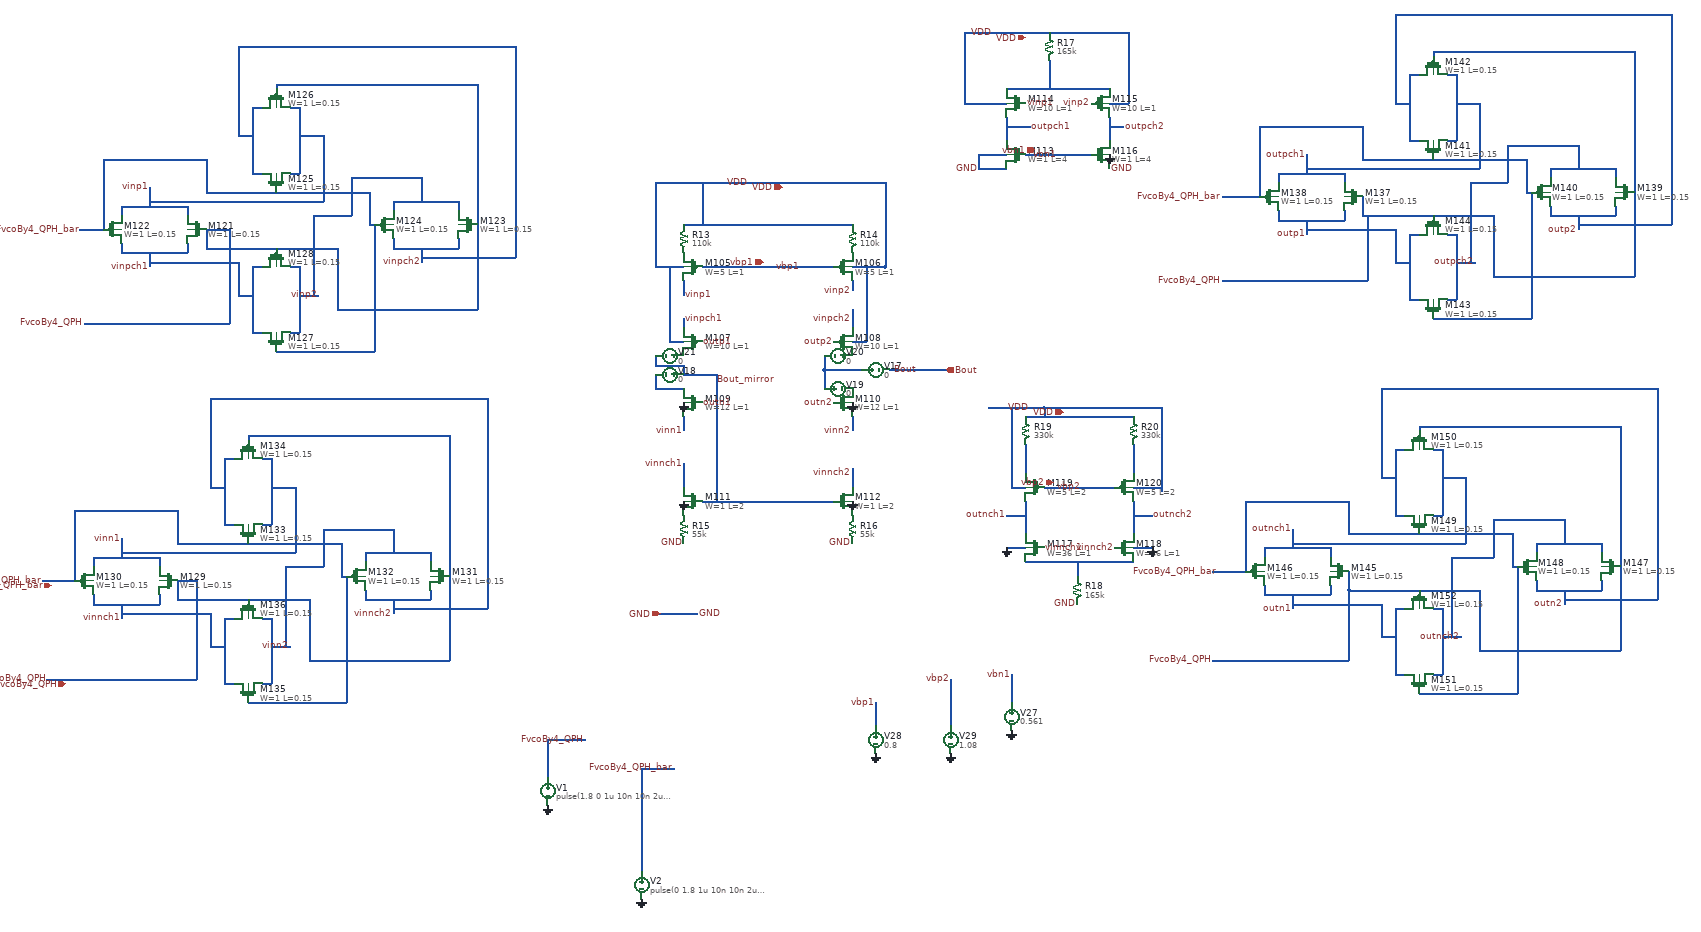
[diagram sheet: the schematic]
v {xschem version=2.9.9 file_version=1.2 }
G {}
K {}
V {}
S {}
E {}
N 3890 4550 4170 4550 { lab=vbp1}
N 3850 4460 4210 4460 { lab=VDD}
N 3790 4550 3850 4550 { lab=VDD}
N 3790 4370 3790 4550 { lab=VDD}
N 3790 4370 3880 4370 { lab=VDD}
N 3880 4370 4280 4370 { lab=VDD}
N 4210 4550 4280 4550 { lab=VDD}
N 4280 4530 4280 4550 { lab=VDD}
N 3890 5050 4170 5050 { lab=Bout_mirror}
N 3850 4780 3920 4780 { lab=Bout_mirror}
N 3920 4780 3920 4910 { lab=Bout_mirror}
N 3820 4710 3850 4710 { lab=VDD}
N 3820 4630 3820 4710 { lab=VDD}
N 4210 4710 4240 4710 { lab=VDD}
N 3890 4370 3890 4460 { lab=VDD}
N 4240 4630 4240 4710 { lab=VDD}
N 4280 4370 4280 4550 { lab=VDD}
N 4210 4770 4230 4770 { lab=#net1}
N 3790 4780 3790 4810 { lab=#net2}
N 3790 4810 3850 4810 { lab=#net2}
N 4150 4740 4150 4770 { lab=#net1}
N 3790 4740 3790 4760 { lab=Bout_mirror}
N 3790 4760 3850 4760 { lab=Bout_mirror}
N 3850 4760 3850 4780 { lab=Bout_mirror}
N 4150 4770 4150 4810 { lab=#net1}
N 4290 4770 4410 4770 { lab=Bout}
N 4580 4310 4720 4310 { lab=vbn1}
N 4760 4230 4760 4280 { lab=outpch2}
N 4540 4230 4540 4280 { lab=outpch1}
N 4540 4170 4760 4170 { lab=#net3}
N 4760 4200 4800 4200 { lab=VDD}
N 4800 4080 4800 4200 { lab=VDD}
N 4450 4200 4540 4200 { lab=VDD}
N 4450 4090 4450 4200 { lab=VDD}
N 4630 4110 4630 4170 { lab=#net3}
N 4450 4060 4450 4090 { lab=VDD}
N 4450 4050 4450 4060 { lab=VDD}
N 4450 4050 4630 4050 { lab=VDD}
N 4630 4050 4800 4050 { lab=VDD}
N 4800 4050 4800 4090 { lab=VDD}
N 4760 4250 4790 4250 { lab=outpch2}
N 4540 4250 4590 4250 { lab=outpch1}
N 4480 4310 4540 4310 { lab=GND}
N 4480 4310 4480 4340 { lab=GND}
N 4480 4340 4540 4340 { lab=GND}
N 4580 5180 4810 5180 { lab=#net4}
N 4690 5180 4690 5210 { lab=#net4}
N 4580 5050 4580 5120 { lab=outnch1}
N 4810 5050 4810 5120 { lab=outnch2}
N 4580 4930 4580 4990 { lab=#net5}
N 4810 4930 4810 4990 { lab=#net6}
N 4580 4870 4810 4870 { lab=VDD}
N 4500 4850 4620 4850 { lab=VDD}
N 4620 4850 4620 4870 { lab=VDD}
N 4620 5020 4770 5020 { lab=vbp2}
N 4540 5150 4580 5150 { lab=GND}
N 4810 5150 4850 5150 { lab=GND}
N 4810 5080 4850 5080 { lab=outnch2}
N 4540 5080 4580 5080 { lab=outnch1}
N 4550 4850 4550 5020 { lab=VDD}
N 4550 5020 4580 5020 { lab=VDD}
N 4620 4850 4870 4850 { lab=VDD}
N 4870 4850 4870 5030 { lab=VDD}
N 4810 5020 4870 5020 { lab=VDD}
N 3920 4910 3920 5050 { lab=Bout_mirror}
N 3850 4660 3850 4680 { lab=vinpch1}
N 4210 4660 4210 4680 { lab=vinpch2}
N 4240 4550 4240 4630 { lab=VDD}
N 3820 4550 3820 4630 { lab=VDD}
N 3850 4870 3850 4900 { lab=vinn1}
N 3850 4980 3850 5020 { lab=vinnch1}
N 4210 4870 4210 4900 { lab=vinn2}
N 4210 5000 4210 5020 { lab=vinnch2}
N 3850 4580 3850 4610 { lab=vinp1}
N 4210 4580 4210 4600 { lab=vinp2}
N 4210 4640 4210 4660 { lab=vinpch2}
N 4150 4770 4220 4770 { lab=#net1}
N 3850 4970 3850 4990 { lab=vinnch1}
N 4210 4980 4210 5010 { lab=vinnch2}
N 2790 4420 2790 4440 { lab=vinp1}
N 2650 4420 2790 4420 { lab=vinp1}
N 2650 4420 2650 4440 { lab=vinp1}
N 2790 4500 2790 4520 { lab=vinpch1}
N 2650 4520 2790 4520 { lab=vinpch1}
N 2650 4500 2650 4520 { lab=vinpch1}
N 2710 4520 2710 4550 { lab=vinpch1}
N 2710 4380 2710 4420 { lab=vinp1}
N 3370 4410 3370 4430 { lab=vinp2}
N 3230 4410 3370 4410 { lab=vinp2}
N 3230 4410 3230 4430 { lab=vinp2}
N 3370 4490 3370 4510 { lab=vinpch2}
N 3230 4510 3370 4510 { lab=vinpch2}
N 3230 4490 3230 4510 { lab=vinpch2}
N 3290 4510 3290 4540 { lab=vinpch2}
N 3290 4370 3290 4410 { lab=vinp2}
N 3010 4350 3030 4350 { lab=vinp1}
N 3030 4210 3030 4350 { lab=vinp1}
N 3010 4210 3030 4210 { lab=vinp1}
N 2930 4350 2950 4350 { lab=vinpch2}
N 2930 4210 2930 4350 { lab=vinpch2}
N 2930 4210 2950 4210 { lab=vinpch2}
N 2900 4270 2930 4270 { lab=vinpch2}
N 3030 4270 3070 4270 { lab=vinp1}
N 3010 4690 3030 4690 { lab=vinp2}
N 3030 4550 3030 4690 { lab=vinp2}
N 3010 4550 3030 4550 { lab=vinp2}
N 2930 4690 2950 4690 { lab=vinpch1}
N 2930 4550 2930 4690 { lab=vinpch1}
N 2930 4550 2950 4550 { lab=vinpch1}
N 2900 4610 2930 4610 { lab=vinpch1}
N 3030 4610 3070 4610 { lab=vinp2}
N 2610 4320 2610 4470 { lab=FvcoBy4_QPH_bar}
N 2610 4320 2830 4320 { lab=FvcoBy4_QPH_bar}
N 2830 4320 2830 4380 { lab=FvcoBy4_QPH_bar}
N 2830 4380 2830 4390 { lab=FvcoBy4_QPH_bar}
N 2830 4390 2980 4390 { lab=FvcoBy4_QPH_bar}
N 2980 4390 3180 4390 { lab=FvcoBy4_QPH_bar}
N 3180 4390 3180 4460 { lab=FvcoBy4_QPH_bar}
N 3180 4460 3190 4460 { lab=FvcoBy4_QPH_bar}
N 3190 4460 3190 4730 { lab=FvcoBy4_QPH_bar}
N 2980 4730 3190 4730 { lab=FvcoBy4_QPH_bar}
N 2830 4470 2830 4510 { lab=FvcoBy4_QPH}
N 2830 4510 2980 4510 { lab=FvcoBy4_QPH}
N 2980 4510 3110 4510 { lab=FvcoBy4_QPH}
N 3110 4510 3110 4640 { lab=FvcoBy4_QPH}
N 3110 4640 3410 4640 { lab=FvcoBy4_QPH}
N 3410 4460 3410 4640 { lab=FvcoBy4_QPH}
N 3410 4160 3410 4460 { lab=FvcoBy4_QPH}
N 2980 4160 3410 4160 { lab=FvcoBy4_QPH}
N 2980 4160 2980 4170 { lab=FvcoBy4_QPH}
N 2710 4410 3080 4410 { lab=vinp1}
N 3080 4270 3080 4410 { lab=vinp1}
N 3070 4270 3080 4270 { lab=vinp1}
N 2710 4540 2900 4540 { lab=vinpch1}
N 2900 4540 2900 4610 { lab=vinpch1}
N 3060 4440 3060 4610 { lab=vinp2}
N 3060 4440 3140 4440 { lab=vinp2}
N 3140 4360 3140 4440 { lab=vinp2}
N 3140 4360 3290 4360 { lab=vinp2}
N 3290 4360 3290 4370 { lab=vinp2}
N 2900 4080 2900 4270 { lab=vinpch2}
N 2900 4080 3490 4080 { lab=vinpch2}
N 3490 4080 3490 4530 { lab=vinpch2}
N 3290 4530 3490 4530 { lab=vinpch2}
N 2730 5170 2730 5190 { lab=vinn1}
N 2590 5170 2730 5170 { lab=vinn1}
N 2590 5170 2590 5190 { lab=vinn1}
N 2730 5250 2730 5270 { lab=vinnch1}
N 2590 5270 2730 5270 { lab=vinnch1}
N 2590 5250 2590 5270 { lab=vinnch1}
N 2650 5270 2650 5300 { lab=vinnch1}
N 2650 5130 2650 5170 { lab=vinn1}
N 3310 5160 3310 5180 { lab=vinn2}
N 3170 5160 3310 5160 { lab=vinn2}
N 3170 5160 3170 5180 { lab=vinn2}
N 3310 5240 3310 5260 { lab=vinnch2}
N 3170 5260 3310 5260 { lab=vinnch2}
N 3170 5240 3170 5260 { lab=vinnch2}
N 3230 5260 3230 5290 { lab=vinnch2}
N 3230 5120 3230 5160 { lab=vinn2}
N 2950 5100 2970 5100 { lab=vinn1}
N 2970 4960 2970 5100 { lab=vinn1}
N 2950 4960 2970 4960 { lab=vinn1}
N 2870 5100 2890 5100 { lab=vinnch2}
N 2870 4960 2870 5100 { lab=vinnch2}
N 2870 4960 2890 4960 { lab=vinnch2}
N 2840 5020 2870 5020 { lab=vinnch2}
N 2970 5020 3010 5020 { lab=vinn1}
N 2950 5440 2970 5440 { lab=vinn2}
N 2970 5300 2970 5440 { lab=vinn2}
N 2950 5300 2970 5300 { lab=vinn2}
N 2870 5440 2890 5440 { lab=vinnch1}
N 2870 5300 2870 5440 { lab=vinnch1}
N 2870 5300 2890 5300 { lab=vinnch1}
N 2840 5360 2870 5360 { lab=vinnch1}
N 2970 5360 3010 5360 { lab=vinn2}
N 2550 5070 2550 5220 { lab=FvcoBy4_QPH_bar}
N 2550 5070 2770 5070 { lab=FvcoBy4_QPH_bar}
N 2770 5070 2770 5130 { lab=FvcoBy4_QPH_bar}
N 2770 5130 2770 5140 { lab=FvcoBy4_QPH_bar}
N 2770 5140 2920 5140 { lab=FvcoBy4_QPH_bar}
N 2920 5140 3120 5140 { lab=FvcoBy4_QPH_bar}
N 3120 5140 3120 5210 { lab=FvcoBy4_QPH_bar}
N 3120 5210 3130 5210 { lab=FvcoBy4_QPH_bar}
N 3130 5210 3130 5480 { lab=FvcoBy4_QPH_bar}
N 2920 5480 3130 5480 { lab=FvcoBy4_QPH_bar}
N 2770 5220 2770 5260 { lab=FvcoBy4_QPH}
N 2770 5260 2920 5260 { lab=FvcoBy4_QPH}
N 2920 5260 3050 5260 { lab=FvcoBy4_QPH}
N 3050 5260 3050 5390 { lab=FvcoBy4_QPH}
N 3050 5390 3350 5390 { lab=FvcoBy4_QPH}
N 3350 5210 3350 5390 { lab=FvcoBy4_QPH}
N 3350 4910 3350 5210 { lab=FvcoBy4_QPH}
N 2920 4910 3350 4910 { lab=FvcoBy4_QPH}
N 2920 4910 2920 4920 { lab=FvcoBy4_QPH}
N 2650 5160 3020 5160 { lab=vinn1}
N 3020 5020 3020 5160 { lab=vinn1}
N 3010 5020 3020 5020 { lab=vinn1}
N 2650 5290 2840 5290 { lab=vinnch1}
N 2840 5290 2840 5360 { lab=vinnch1}
N 3000 5190 3000 5360 { lab=vinn2}
N 3000 5190 3080 5190 { lab=vinn2}
N 3080 5110 3080 5190 { lab=vinn2}
N 3080 5110 3230 5110 { lab=vinn2}
N 3230 5110 3230 5120 { lab=vinn2}
N 2840 4830 2840 5020 { lab=vinnch2}
N 2840 4830 3430 4830 { lab=vinnch2}
N 3430 4830 3430 5280 { lab=vinnch2}
N 3230 5280 3430 5280 { lab=vinnch2}
N 5260 4350 5260 4370 { lab=outpch1}
N 5120 4350 5260 4350 { lab=outpch1}
N 5120 4350 5120 4370 { lab=outpch1}
N 5260 4430 5260 4450 { lab=outp1}
N 5120 4450 5260 4450 { lab=outp1}
N 5120 4430 5120 4450 { lab=outp1}
N 5180 4450 5180 4480 { lab=outp1}
N 5180 4310 5180 4350 { lab=outpch1}
N 5840 4340 5840 4360 { lab=outpch2}
N 5700 4340 5840 4340 { lab=outpch2}
N 5700 4340 5700 4360 { lab=outpch2}
N 5840 4420 5840 4440 { lab=outp2}
N 5700 4440 5840 4440 { lab=outp2}
N 5700 4420 5700 4440 { lab=outp2}
N 5760 4440 5760 4470 { lab=outp2}
N 5760 4300 5760 4340 { lab=outpch2}
N 5480 4280 5500 4280 { lab=outpch1}
N 5500 4140 5500 4280 { lab=outpch1}
N 5480 4140 5500 4140 { lab=outpch1}
N 5400 4280 5420 4280 { lab=outp2}
N 5400 4140 5400 4280 { lab=outp2}
N 5400 4140 5420 4140 { lab=outp2}
N 5370 4200 5400 4200 { lab=outp2}
N 5500 4200 5540 4200 { lab=outpch1}
N 5480 4620 5500 4620 { lab=outpch2}
N 5500 4480 5500 4620 { lab=outpch2}
N 5480 4480 5500 4480 { lab=outpch2}
N 5400 4620 5420 4620 { lab=outp1}
N 5400 4480 5400 4620 { lab=outp1}
N 5400 4480 5420 4480 { lab=outp1}
N 5370 4540 5400 4540 { lab=outp1}
N 5500 4540 5540 4540 { lab=outpch2}
N 5080 4250 5080 4400 { lab=FvcoBy4_QPH_bar}
N 5080 4250 5300 4250 { lab=FvcoBy4_QPH_bar}
N 5300 4250 5300 4310 { lab=FvcoBy4_QPH_bar}
N 5300 4310 5300 4320 { lab=FvcoBy4_QPH_bar}
N 5300 4320 5450 4320 { lab=FvcoBy4_QPH_bar}
N 5450 4320 5650 4320 { lab=FvcoBy4_QPH_bar}
N 5650 4320 5650 4390 { lab=FvcoBy4_QPH_bar}
N 5650 4390 5660 4390 { lab=FvcoBy4_QPH_bar}
N 5660 4390 5660 4660 { lab=FvcoBy4_QPH_bar}
N 5450 4660 5660 4660 { lab=FvcoBy4_QPH_bar}
N 5300 4400 5300 4440 { lab=FvcoBy4_QPH}
N 5300 4440 5450 4440 { lab=FvcoBy4_QPH}
N 5450 4440 5580 4440 { lab=FvcoBy4_QPH}
N 5580 4440 5580 4570 { lab=FvcoBy4_QPH}
N 5580 4570 5880 4570 { lab=FvcoBy4_QPH}
N 5880 4390 5880 4570 { lab=FvcoBy4_QPH}
N 5880 4090 5880 4390 { lab=FvcoBy4_QPH}
N 5450 4090 5880 4090 { lab=FvcoBy4_QPH}
N 5450 4090 5450 4100 { lab=FvcoBy4_QPH}
N 5180 4340 5550 4340 { lab=outpch1}
N 5550 4200 5550 4340 { lab=outpch1}
N 5540 4200 5550 4200 { lab=outpch1}
N 5180 4470 5370 4470 { lab=outp1}
N 5370 4470 5370 4540 { lab=outp1}
N 5530 4370 5530 4540 { lab=outpch2}
N 5530 4370 5610 4370 { lab=outpch2}
N 5610 4290 5610 4370 { lab=outpch2}
N 5610 4290 5760 4290 { lab=outpch2}
N 5760 4290 5760 4300 { lab=outpch2}
N 5370 4010 5370 4200 { lab=outp2}
N 5370 4010 5960 4010 { lab=outp2}
N 5960 4010 5960 4460 { lab=outp2}
N 5760 4460 5960 4460 { lab=outp2}
N 5230 5150 5230 5170 { lab=outnch1}
N 5090 5150 5230 5150 { lab=outnch1}
N 5090 5150 5090 5170 { lab=outnch1}
N 5230 5230 5230 5250 { lab=outn1}
N 5090 5250 5230 5250 { lab=outn1}
N 5090 5230 5090 5250 { lab=outn1}
N 5150 5250 5150 5280 { lab=outn1}
N 5150 5110 5150 5150 { lab=outnch1}
N 5810 5140 5810 5160 { lab=outnch2}
N 5670 5140 5810 5140 { lab=outnch2}
N 5670 5140 5670 5160 { lab=outnch2}
N 5810 5220 5810 5240 { lab=outn2}
N 5670 5240 5810 5240 { lab=outn2}
N 5670 5220 5670 5240 { lab=outn2}
N 5730 5240 5730 5270 { lab=outn2}
N 5730 5100 5730 5140 { lab=outnch2}
N 5450 5080 5470 5080 { lab=outnch1}
N 5470 4940 5470 5080 { lab=outnch1}
N 5450 4940 5470 4940 { lab=outnch1}
N 5370 5080 5390 5080 { lab=outn2}
N 5370 4940 5370 5080 { lab=outn2}
N 5370 4940 5390 4940 { lab=outn2}
N 5340 5000 5370 5000 { lab=outn2}
N 5470 5000 5510 5000 { lab=outnch1}
N 5450 5420 5470 5420 { lab=outnch2}
N 5470 5280 5470 5420 { lab=outnch2}
N 5450 5280 5470 5280 { lab=outnch2}
N 5370 5420 5390 5420 { lab=outn1}
N 5370 5280 5370 5420 { lab=outn1}
N 5370 5280 5390 5280 { lab=outn1}
N 5340 5340 5370 5340 { lab=outn1}
N 5470 5340 5510 5340 { lab=outnch2}
N 5050 5050 5050 5200 { lab=FvcoBy4_QPH_bar}
N 5050 5050 5270 5050 { lab=FvcoBy4_QPH_bar}
N 5270 5050 5270 5110 { lab=FvcoBy4_QPH_bar}
N 5270 5110 5270 5120 { lab=FvcoBy4_QPH_bar}
N 5270 5120 5420 5120 { lab=FvcoBy4_QPH_bar}
N 5420 5120 5620 5120 { lab=FvcoBy4_QPH_bar}
N 5620 5120 5620 5190 { lab=FvcoBy4_QPH_bar}
N 5620 5190 5630 5190 { lab=FvcoBy4_QPH_bar}
N 5630 5190 5630 5460 { lab=FvcoBy4_QPH_bar}
N 5420 5460 5630 5460 { lab=FvcoBy4_QPH_bar}
N 5270 5200 5270 5240 { lab=FvcoBy4_QPH}
N 5270 5240 5420 5240 { lab=FvcoBy4_QPH}
N 5420 5240 5550 5240 { lab=FvcoBy4_QPH}
N 5550 5240 5550 5370 { lab=FvcoBy4_QPH}
N 5550 5370 5850 5370 { lab=FvcoBy4_QPH}
N 5850 5190 5850 5370 { lab=FvcoBy4_QPH}
N 5850 4890 5850 5190 { lab=FvcoBy4_QPH}
N 5420 4890 5850 4890 { lab=FvcoBy4_QPH}
N 5420 4890 5420 4900 { lab=FvcoBy4_QPH}
N 5150 5140 5520 5140 { lab=outnch1}
N 5520 5000 5520 5140 { lab=outnch1}
N 5510 5000 5520 5000 { lab=outnch1}
N 5150 5270 5340 5270 { lab=outn1}
N 5340 5270 5340 5340 { lab=outn1}
N 5490 5170 5490 5340 { lab=outnch2}
N 5500 5170 5580 5170 { lab=outnch2}
N 5580 5090 5580 5170 { lab=outnch2}
N 5580 5090 5730 5090 { lab=outnch2}
N 5730 5090 5730 5100 { lab=outnch2}
N 5340 4810 5340 5000 { lab=outn2}
N 5340 4810 5930 4810 { lab=outn2}
N 5930 4810 5930 5260 { lab=outn2}
N 5730 5260 5930 5260 { lab=outn2}
N 5490 5170 5540 5170 { lab=outnch2}
N 2830 4470 2880 4470 { lab=FvcoBy4_QPH}
N 2880 4470 2880 4670 { lab=FvcoBy4_QPH}
N 2570 4670 2880 4670 { lab=FvcoBy4_QPH}
N 2560 4470 2610 4470 { lab=FvcoBy4_QPH_bar}
N 2480 5220 2550 5220 { lab=FvcoBy4_QPH_bar}
N 2770 5220 2810 5220 { lab=FvcoBy4_QPH}
N 2810 5220 2810 5430 { lab=FvcoBy4_QPH}
N 2490 5430 2810 5430 { lab=FvcoBy4_QPH}
N 5000 4400 5080 4400 { lab=FvcoBy4_QPH_bar}
N 5310 4440 5310 4580 { lab=FvcoBy4_QPH}
N 5000 4580 5310 4580 { lab=FvcoBy4_QPH}
N 4980 5200 5050 5200 { lab=FvcoBy4_QPH_bar}
N 5270 5240 5270 5390 { lab=FvcoBy4_QPH}
N 4980 5390 5270 5390 { lab=FvcoBy4_QPH}
N 3790 5290 3880 5290 { lab=GND}
N 3760 5620 3830 5620 { lab=#net7}
N 4420 5430 4420 5530 { lab=vbp2}
N 3760 5620 3760 5840 { lab=#net7}
N 3560 5560 3560 5640 { lab=#net8}
N 3560 5560 3640 5560 { lab=#net8}
N 4260 5480 4260 5530 { lab=vbp1}
N 4550 5420 4550 5480 { lab=vbn1}
C {xschem_sky130/sky130_fd_pr/pfet_01v8_lvt.sym} 3870 4550 0 1 {name=M105
L=1
W=5
nf=1
mult=1
ad="'int((nf+1)/2) * W/nf * 0.29'" 
pd="'2*int((nf+1)/2) * (W/nf + 0.29)'"
as="'int((nf+2)/2) * W/nf * 0.29'" 
ps="'2*int((nf+2)/2) * (W/nf + 0.29)'"
nrd="'0.29 / W'" nrs="'0.29 / W'"
sa=0 sb=0 sd=0
model=pfet_01v8_lvt
spiceprefix=X
}
C {res.sym} 3850 4490 0 1 {name=R13
value=110k
footprint=1206
device=resistor
m=1}
C {xschem_sky130/sky130_fd_pr/pfet_01v8_lvt.sym} 4190 4550 0 0 {name=M106
L=1
W=5
nf=1
mult=1
ad="'int((nf+1)/2) * W/nf * 0.29'" 
pd="'2*int((nf+1)/2) * (W/nf + 0.29)'"
as="'int((nf+2)/2) * W/nf * 0.29'" 
ps="'2*int((nf+2)/2) * (W/nf + 0.29)'"
nrd="'0.29 / W'" nrs="'0.29 / W'"
sa=0 sb=0 sd=0
model=pfet_01v8_lvt
spiceprefix=X
}
C {res.sym} 4210 4490 0 0 {name=R14
value=110k
footprint=1206
device=resistor
m=1}
C {xschem_sky130/sky130_fd_pr/pfet_01v8_lvt.sym} 3870 4710 0 1 {name=M107
L=1
W=10
nf=1
mult=1
ad="'int((nf+1)/2) * W/nf * 0.29'" 
pd="'2*int((nf+1)/2) * (W/nf + 0.29)'"
as="'int((nf+2)/2) * W/nf * 0.29'" 
ps="'2*int((nf+2)/2) * (W/nf + 0.29)'"
nrd="'0.29 / W'" nrs="'0.29 / W'"
sa=0 sb=0 sd=0
model=pfet_01v8_lvt
spiceprefix=X
}
C {xschem_sky130/sky130_fd_pr/pfet_01v8_lvt.sym} 4190 4710 0 0 {name=M108
L=1
W=10
nf=1
mult=1
ad="'int((nf+1)/2) * W/nf * 0.29'" 
pd="'2*int((nf+1)/2) * (W/nf + 0.29)'"
as="'int((nf+2)/2) * W/nf * 0.29'" 
ps="'2*int((nf+2)/2) * (W/nf + 0.29)'"
nrd="'0.29 / W'" nrs="'0.29 / W'"
sa=0 sb=0 sd=0
model=pfet_01v8_lvt
spiceprefix=X
}
C {xschem_sky130/sky130_fd_pr/nfet_01v8_lvt.sym} 3870 4840 0 1 {name=M109
L=1
W=12
nf=1
mult=1
ad="'int((nf+1)/2) * W/nf * 0.29'" 
pd="'2*int((nf+1)/2) * (W/nf + 0.29)'"
as="'int((nf+2)/2) * W/nf * 0.29'" 
ps="'2*int((nf+2)/2) * (W/nf + 0.29)'"
nrd="'0.29 / W'" nrs="'0.29 / W'"
sa=0 sb=0 sd=0
model=nfet_01v8_lvt
spiceprefix=X
}
C {xschem_sky130/sky130_fd_pr/nfet_01v8_lvt.sym} 4190 4840 0 0 {name=M110
L=1
W=12
nf=1
mult=1
ad="'int((nf+1)/2) * W/nf * 0.29'" 
pd="'2*int((nf+1)/2) * (W/nf + 0.29)'"
as="'int((nf+2)/2) * W/nf * 0.29'" 
ps="'2*int((nf+2)/2) * (W/nf + 0.29)'"
nrd="'0.29 / W'" nrs="'0.29 / W'"
sa=0 sb=0 sd=0
model=nfet_01v8_lvt
spiceprefix=X
}
C {xschem_sky130/sky130_fd_pr/nfet_01v8_lvt.sym} 3870 5050 0 1 {name=M111
L=2
W=1
nf=1
mult=1
ad="'int((nf+1)/2) * W/nf * 0.29'" 
pd="'2*int((nf+1)/2) * (W/nf + 0.29)'"
as="'int((nf+2)/2) * W/nf * 0.29'" 
ps="'2*int((nf+2)/2) * (W/nf + 0.29)'"
nrd="'0.29 / W'" nrs="'0.29 / W'"
sa=0 sb=0 sd=0
model=nfet_01v8_lvt
spiceprefix=X
}
C {xschem_sky130/sky130_fd_pr/nfet_01v8_lvt.sym} 4190 5050 0 0 {name=M112
L=2
W=1
nf=1
mult=1
ad="'int((nf+1)/2) * W/nf * 0.29'" 
pd="'2*int((nf+1)/2) * (W/nf + 0.29)'"
as="'int((nf+2)/2) * W/nf * 0.29'" 
ps="'2*int((nf+2)/2) * (W/nf + 0.29)'"
nrd="'0.29 / W'" nrs="'0.29 / W'"
sa=0 sb=0 sd=0
model=nfet_01v8_lvt
spiceprefix=X
}
C {gnd.sym} 4210 5050 3 0 {name=l152 lab=GND}
C {gnd.sym} 3850 5050 1 0 {name=l161 lab=GND}
C {gnd.sym} 3850 4840 1 0 {name=l167 lab=GND}
C {gnd.sym} 4210 4840 3 0 {name=l168 lab=GND}
C {res.sym} 3850 5110 0 1 {name=R15
value=55k
footprint=1206
device=resistor
m=1}
C {res.sym} 4210 5110 0 1 {name=R16
value=55k
footprint=1206
device=resistor
m=1}
C {vsource.sym} 4260 4770 3 0 {name=V17 value=0}
C {vsource.sym} 3820 4780 1 0 {name=V18 value=0}
C {vsource.sym} 4180 4810 3 0 {name=V19 value=0}
C {vsource.sym} 4180 4740 1 0 {name=V20 value=0}
C {vsource.sym} 3820 4740 1 0 {name=V21 value=0}
C {xschem_sky130/sky130_fd_pr/nfet_01v8_lvt.sym} 4560 4310 0 1 {name=M113
L=4
W=1
nf=1
mult=1
ad="'int((nf+1)/2) * W/nf * 0.29'" 
pd="'2*int((nf+1)/2) * (W/nf + 0.29)'"
as="'int((nf+2)/2) * W/nf * 0.29'" 
ps="'2*int((nf+2)/2) * (W/nf + 0.29)'"
nrd="'0.29 / W'" nrs="'0.29 / W'"
sa=0 sb=0 sd=0
model=nfet_01v8_lvt
spiceprefix=X
}
C {xschem_sky130/sky130_fd_pr/pfet_01v8_lvt.sym} 4560 4200 0 1 {name=M114
L=1
W=10
nf=1
mult=1
ad="'int((nf+1)/2) * W/nf * 0.29'" 
pd="'2*int((nf+1)/2) * (W/nf + 0.29)'"
as="'int((nf+2)/2) * W/nf * 0.29'" 
ps="'2*int((nf+2)/2) * (W/nf + 0.29)'"
nrd="'0.29 / W'" nrs="'0.29 / W'"
sa=0 sb=0 sd=0
model=pfet_01v8_lvt
spiceprefix=X
}
C {xschem_sky130/sky130_fd_pr/pfet_01v8_lvt.sym} 4740 4200 0 0 {name=M115
L=1
W=10
nf=1
mult=1
ad="'int((nf+1)/2) * W/nf * 0.29'" 
pd="'2*int((nf+1)/2) * (W/nf + 0.29)'"
as="'int((nf+2)/2) * W/nf * 0.29'" 
ps="'2*int((nf+2)/2) * (W/nf + 0.29)'"
nrd="'0.29 / W'" nrs="'0.29 / W'"
sa=0 sb=0 sd=0
model=pfet_01v8_lvt
spiceprefix=X
}
C {xschem_sky130/sky130_fd_pr/nfet_01v8_lvt.sym} 4740 4310 0 0 {name=M116
L=4
W=1
nf=1
mult=1
ad="'int((nf+1)/2) * W/nf * 0.29'" 
pd="'2*int((nf+1)/2) * (W/nf + 0.29)'"
as="'int((nf+2)/2) * W/nf * 0.29'" 
ps="'2*int((nf+2)/2) * (W/nf + 0.29)'"
nrd="'0.29 / W'" nrs="'0.29 / W'"
sa=0 sb=0 sd=0
model=nfet_01v8_lvt
spiceprefix=X
}
C {gnd.sym} 4760 4310 3 0 {name=l175 lab=GND}
C {res.sym} 4630 4080 0 0 {name=R17
value=165k
footprint=1206
device=resistor
m=1}
C {xschem_sky130/sky130_fd_pr/nfet_01v8_lvt.sym} 4600 5150 0 1 {name=M117
L=1
W=36
nf=1
mult=1
ad="'int((nf+1)/2) * W/nf * 0.29'" 
pd="'2*int((nf+1)/2) * (W/nf + 0.29)'"
as="'int((nf+2)/2) * W/nf * 0.29'" 
ps="'2*int((nf+2)/2) * (W/nf + 0.29)'"
nrd="'0.29 / W'" nrs="'0.29 / W'"
sa=0 sb=0 sd=0
model=nfet_01v8_lvt
spiceprefix=X
}
C {xschem_sky130/sky130_fd_pr/nfet_01v8_lvt.sym} 4790 5150 0 0 {name=M118
L=1
W=36
nf=1
mult=1
ad="'int((nf+1)/2) * W/nf * 0.29'" 
pd="'2*int((nf+1)/2) * (W/nf + 0.29)'"
as="'int((nf+2)/2) * W/nf * 0.29'" 
ps="'2*int((nf+2)/2) * (W/nf + 0.29)'"
nrd="'0.29 / W'" nrs="'0.29 / W'"
sa=0 sb=0 sd=0
model=nfet_01v8_lvt
spiceprefix=X
}
C {xschem_sky130/sky130_fd_pr/pfet_01v8_lvt.sym} 4600 5020 0 1 {name=M119
L=2
W=5
nf=1
mult=1
ad="'int((nf+1)/2) * W/nf * 0.29'" 
pd="'2*int((nf+1)/2) * (W/nf + 0.29)'"
as="'int((nf+2)/2) * W/nf * 0.29'" 
ps="'2*int((nf+2)/2) * (W/nf + 0.29)'"
nrd="'0.29 / W'" nrs="'0.29 / W'"
sa=0 sb=0 sd=0
model=pfet_01v8_lvt
spiceprefix=X
}
C {xschem_sky130/sky130_fd_pr/pfet_01v8_lvt.sym} 4790 5020 0 0 {name=M120
L=2
W=5
nf=1
mult=1
ad="'int((nf+1)/2) * W/nf * 0.29'" 
pd="'2*int((nf+1)/2) * (W/nf + 0.29)'"
as="'int((nf+2)/2) * W/nf * 0.29'" 
ps="'2*int((nf+2)/2) * (W/nf + 0.29)'"
nrd="'0.29 / W'" nrs="'0.29 / W'"
sa=0 sb=0 sd=0
model=pfet_01v8_lvt
spiceprefix=X
}
C {res.sym} 4690 5240 0 0 {name=R18
value=165k
footprint=1206
device=resistor
m=1}
C {res.sym} 4580 4900 0 0 {name=R19
value=330k
footprint=1206
device=resistor
m=1}
C {res.sym} 4810 4900 0 0 {name=R20
value=330k
footprint=1206
device=resistor
m=1}
C {gnd.sym} 4850 5150 0 0 {name=l181 lab=GND}
C {gnd.sym} 4540 5150 0 0 {name=l182 lab=GND}
C {lab_pin.sym} 4580 4200 2 0 {name=l183 sig_type=std_logic lab=vinp1}
C {lab_pin.sym} 4720 4200 0 0 {name=l184 sig_type=std_logic lab=vinp2}
C {lab_pin.sym} 4790 4250 2 0 {name=l185 sig_type=std_logic lab=outpch2}
C {lab_pin.sym} 4590 4250 2 0 {name=l186 sig_type=std_logic lab=outpch1}
C {lab_pin.sym} 3850 4610 2 0 {name=l187 sig_type=std_logic lab=vinp1}
C {lab_pin.sym} 4210 4600 0 0 {name=l188 sig_type=std_logic lab=vinp2}
C {lab_pin.sym} 3890 4710 2 0 {name=l189 sig_type=std_logic lab=outp1}
C {lab_pin.sym} 4170 4710 0 0 {name=l190 sig_type=std_logic lab=outp2}
C {lab_pin.sym} 4620 5150 2 0 {name=l191 sig_type=std_logic lab=vinnch1}
C {lab_pin.sym} 4770 5150 0 0 {name=l192 sig_type=std_logic lab=vinnch2}
C {lab_pin.sym} 4540 5080 0 0 {name=l193 sig_type=std_logic lab=outnch1}
C {lab_pin.sym} 4850 5080 2 0 {name=l194 sig_type=std_logic lab=outnch2}
C {lab_pin.sym} 3890 4840 2 0 {name=l195 sig_type=std_logic lab=outn1}
C {lab_pin.sym} 4170 4840 0 0 {name=l196 sig_type=std_logic lab=outn2}
C {lab_pin.sym} 3920 4790 2 0 {name=l197 sig_type=std_logic lab=Bout_mirror}
C {lab_pin.sym} 3850 4900 0 0 {name=l199 sig_type=std_logic lab=vinn1}
C {lab_pin.sym} 4210 4900 0 0 {name=l200 sig_type=std_logic lab=vinn2}
C {lab_pin.sym} 3850 4970 0 0 {name=l201 sig_type=std_logic lab=vinnch1}
C {lab_pin.sym} 4210 4990 0 0 {name=l202 sig_type=std_logic lab=vinnch2}
C {lab_pin.sym} 3850 4660 2 0 {name=l203 sig_type=std_logic lab=vinpch1}
C {lab_pin.sym} 4210 4660 0 0 {name=l204 sig_type=std_logic lab=vinpch2}
C {xschem_sky130/sky130_fd_pr/nfet3_01v8.sym} 2810 4470 0 1 {name=M121
L=0.15
W=1
body=GND
nf=1
mult=1
ad="'int((nf+1)/2) * W/nf * 0.29'" 
pd="'2*int((nf+1)/2) * (W/nf + 0.29)'"
as="'int((nf+2)/2) * W/nf * 0.29'" 
ps="'2*int((nf+2)/2) * (W/nf + 0.29)'"
nrd="'0.29 / W'" nrs="'0.29 / W'"
sa=0 sb=0 sd=0
model=nfet_01v8
spiceprefix=X
}
C {xschem_sky130/sky130_fd_pr/pfet3_01v8.sym} 2630 4470 0 0 {name=M122
L=0.15
W=1
body=VDD
nf=1
mult=2
ad="'int((nf+1)/2) * W/nf * 0.29'" 
pd="'2*int((nf+1)/2) * (W/nf + 0.29)'"
as="'int((nf+2)/2) * W/nf * 0.29'" 
ps="'2*int((nf+2)/2) * (W/nf + 0.29)'"
nrd="'0.29 / W'" nrs="'0.29 / W'"
sa=0 sb=0 sd=0
model=pfet_01v8
spiceprefix=X
}
C {xschem_sky130/sky130_fd_pr/nfet3_01v8.sym} 3390 4460 0 1 {name=M123
L=0.15
W=1
body=GND
nf=1
mult=1
ad="'int((nf+1)/2) * W/nf * 0.29'" 
pd="'2*int((nf+1)/2) * (W/nf + 0.29)'"
as="'int((nf+2)/2) * W/nf * 0.29'" 
ps="'2*int((nf+2)/2) * (W/nf + 0.29)'"
nrd="'0.29 / W'" nrs="'0.29 / W'"
sa=0 sb=0 sd=0
model=nfet_01v8
spiceprefix=X
}
C {xschem_sky130/sky130_fd_pr/pfet3_01v8.sym} 3210 4460 0 0 {name=M124
L=0.15
W=1
body=VDD
nf=1
mult=2
ad="'int((nf+1)/2) * W/nf * 0.29'" 
pd="'2*int((nf+1)/2) * (W/nf + 0.29)'"
as="'int((nf+2)/2) * W/nf * 0.29'" 
ps="'2*int((nf+2)/2) * (W/nf + 0.29)'"
nrd="'0.29 / W'" nrs="'0.29 / W'"
sa=0 sb=0 sd=0
model=pfet_01v8
spiceprefix=X
}
C {xschem_sky130/sky130_fd_pr/nfet3_01v8.sym} 2980 4370 1 1 {name=M125
L=0.15
W=1
body=GND
nf=1
mult=1
ad="'int((nf+1)/2) * W/nf * 0.29'" 
pd="'2*int((nf+1)/2) * (W/nf + 0.29)'"
as="'int((nf+2)/2) * W/nf * 0.29'" 
ps="'2*int((nf+2)/2) * (W/nf + 0.29)'"
nrd="'0.29 / W'" nrs="'0.29 / W'"
sa=0 sb=0 sd=0
model=nfet_01v8
spiceprefix=X
}
C {xschem_sky130/sky130_fd_pr/pfet3_01v8.sym} 2980 4190 1 0 {name=M126
L=0.15
W=1
body=VDD
nf=1
mult=2
ad="'int((nf+1)/2) * W/nf * 0.29'" 
pd="'2*int((nf+1)/2) * (W/nf + 0.29)'"
as="'int((nf+2)/2) * W/nf * 0.29'" 
ps="'2*int((nf+2)/2) * (W/nf + 0.29)'"
nrd="'0.29 / W'" nrs="'0.29 / W'"
sa=0 sb=0 sd=0
model=pfet_01v8
spiceprefix=X
}
C {xschem_sky130/sky130_fd_pr/nfet3_01v8.sym} 2980 4710 1 1 {name=M127
L=0.15
W=1
body=GND
nf=1
mult=1
ad="'int((nf+1)/2) * W/nf * 0.29'" 
pd="'2*int((nf+1)/2) * (W/nf + 0.29)'"
as="'int((nf+2)/2) * W/nf * 0.29'" 
ps="'2*int((nf+2)/2) * (W/nf + 0.29)'"
nrd="'0.29 / W'" nrs="'0.29 / W'"
sa=0 sb=0 sd=0
model=nfet_01v8
spiceprefix=X
}
C {xschem_sky130/sky130_fd_pr/pfet3_01v8.sym} 2980 4530 1 0 {name=M128
L=0.15
W=1
body=VDD
nf=1
mult=2
ad="'int((nf+1)/2) * W/nf * 0.29'" 
pd="'2*int((nf+1)/2) * (W/nf + 0.29)'"
as="'int((nf+2)/2) * W/nf * 0.29'" 
ps="'2*int((nf+2)/2) * (W/nf + 0.29)'"
nrd="'0.29 / W'" nrs="'0.29 / W'"
sa=0 sb=0 sd=0
model=pfet_01v8
spiceprefix=X
}
C {lab_pin.sym} 2710 4380 1 0 {name=l205 sig_type=std_logic lab=vinp1}
C {lab_pin.sym} 2710 4550 3 0 {name=l206 sig_type=std_logic lab=vinpch1}
C {lab_pin.sym} 3070 4610 1 0 {name=l207 sig_type=std_logic lab=vinp2}
C {lab_pin.sym} 3290 4540 3 0 {name=l208 sig_type=std_logic lab=vinpch2}
C {xschem_sky130/sky130_fd_pr/nfet3_01v8.sym} 2750 5220 0 1 {name=M129
L=0.15
W=1
body=GND
nf=1
mult=1
ad="'int((nf+1)/2) * W/nf * 0.29'" 
pd="'2*int((nf+1)/2) * (W/nf + 0.29)'"
as="'int((nf+2)/2) * W/nf * 0.29'" 
ps="'2*int((nf+2)/2) * (W/nf + 0.29)'"
nrd="'0.29 / W'" nrs="'0.29 / W'"
sa=0 sb=0 sd=0
model=nfet_01v8
spiceprefix=X
}
C {xschem_sky130/sky130_fd_pr/pfet3_01v8.sym} 2570 5220 0 0 {name=M130
L=0.15
W=1
body=VDD
nf=1
mult=2
ad="'int((nf+1)/2) * W/nf * 0.29'" 
pd="'2*int((nf+1)/2) * (W/nf + 0.29)'"
as="'int((nf+2)/2) * W/nf * 0.29'" 
ps="'2*int((nf+2)/2) * (W/nf + 0.29)'"
nrd="'0.29 / W'" nrs="'0.29 / W'"
sa=0 sb=0 sd=0
model=pfet_01v8
spiceprefix=X
}
C {xschem_sky130/sky130_fd_pr/nfet3_01v8.sym} 3330 5210 0 1 {name=M131
L=0.15
W=1
body=GND
nf=1
mult=1
ad="'int((nf+1)/2) * W/nf * 0.29'" 
pd="'2*int((nf+1)/2) * (W/nf + 0.29)'"
as="'int((nf+2)/2) * W/nf * 0.29'" 
ps="'2*int((nf+2)/2) * (W/nf + 0.29)'"
nrd="'0.29 / W'" nrs="'0.29 / W'"
sa=0 sb=0 sd=0
model=nfet_01v8
spiceprefix=X
}
C {xschem_sky130/sky130_fd_pr/pfet3_01v8.sym} 3150 5210 0 0 {name=M132
L=0.15
W=1
body=VDD
nf=1
mult=2
ad="'int((nf+1)/2) * W/nf * 0.29'" 
pd="'2*int((nf+1)/2) * (W/nf + 0.29)'"
as="'int((nf+2)/2) * W/nf * 0.29'" 
ps="'2*int((nf+2)/2) * (W/nf + 0.29)'"
nrd="'0.29 / W'" nrs="'0.29 / W'"
sa=0 sb=0 sd=0
model=pfet_01v8
spiceprefix=X
}
C {xschem_sky130/sky130_fd_pr/nfet3_01v8.sym} 2920 5120 1 1 {name=M133
L=0.15
W=1
body=GND
nf=1
mult=1
ad="'int((nf+1)/2) * W/nf * 0.29'" 
pd="'2*int((nf+1)/2) * (W/nf + 0.29)'"
as="'int((nf+2)/2) * W/nf * 0.29'" 
ps="'2*int((nf+2)/2) * (W/nf + 0.29)'"
nrd="'0.29 / W'" nrs="'0.29 / W'"
sa=0 sb=0 sd=0
model=nfet_01v8
spiceprefix=X
}
C {xschem_sky130/sky130_fd_pr/pfet3_01v8.sym} 2920 4940 1 0 {name=M134
L=0.15
W=1
body=VDD
nf=1
mult=2
ad="'int((nf+1)/2) * W/nf * 0.29'" 
pd="'2*int((nf+1)/2) * (W/nf + 0.29)'"
as="'int((nf+2)/2) * W/nf * 0.29'" 
ps="'2*int((nf+2)/2) * (W/nf + 0.29)'"
nrd="'0.29 / W'" nrs="'0.29 / W'"
sa=0 sb=0 sd=0
model=pfet_01v8
spiceprefix=X
}
C {xschem_sky130/sky130_fd_pr/nfet3_01v8.sym} 2920 5460 1 1 {name=M135
L=0.15
W=1
body=GND
nf=1
mult=1
ad="'int((nf+1)/2) * W/nf * 0.29'" 
pd="'2*int((nf+1)/2) * (W/nf + 0.29)'"
as="'int((nf+2)/2) * W/nf * 0.29'" 
ps="'2*int((nf+2)/2) * (W/nf + 0.29)'"
nrd="'0.29 / W'" nrs="'0.29 / W'"
sa=0 sb=0 sd=0
model=nfet_01v8
spiceprefix=X
}
C {xschem_sky130/sky130_fd_pr/pfet3_01v8.sym} 2920 5280 1 0 {name=M136
L=0.15
W=1
body=VDD
nf=1
mult=2
ad="'int((nf+1)/2) * W/nf * 0.29'" 
pd="'2*int((nf+1)/2) * (W/nf + 0.29)'"
as="'int((nf+2)/2) * W/nf * 0.29'" 
ps="'2*int((nf+2)/2) * (W/nf + 0.29)'"
nrd="'0.29 / W'" nrs="'0.29 / W'"
sa=0 sb=0 sd=0
model=pfet_01v8
spiceprefix=X
}
C {lab_pin.sym} 2650 5130 1 0 {name=l209 sig_type=std_logic lab=vinn1}
C {lab_pin.sym} 2650 5300 3 0 {name=l210 sig_type=std_logic lab=vinnch1}
C {lab_pin.sym} 3010 5360 1 0 {name=l211 sig_type=std_logic lab=vinn2}
C {lab_pin.sym} 3230 5290 3 0 {name=l212 sig_type=std_logic lab=vinnch2}
C {xschem_sky130/sky130_fd_pr/nfet3_01v8.sym} 5280 4400 0 1 {name=M137
L=0.15
W=1
body=GND
nf=1
mult=1
ad="'int((nf+1)/2) * W/nf * 0.29'" 
pd="'2*int((nf+1)/2) * (W/nf + 0.29)'"
as="'int((nf+2)/2) * W/nf * 0.29'" 
ps="'2*int((nf+2)/2) * (W/nf + 0.29)'"
nrd="'0.29 / W'" nrs="'0.29 / W'"
sa=0 sb=0 sd=0
model=nfet_01v8
spiceprefix=X
}
C {xschem_sky130/sky130_fd_pr/pfet3_01v8.sym} 5100 4400 0 0 {name=M138
L=0.15
W=1
body=VDD
nf=1
mult=2
ad="'int((nf+1)/2) * W/nf * 0.29'" 
pd="'2*int((nf+1)/2) * (W/nf + 0.29)'"
as="'int((nf+2)/2) * W/nf * 0.29'" 
ps="'2*int((nf+2)/2) * (W/nf + 0.29)'"
nrd="'0.29 / W'" nrs="'0.29 / W'"
sa=0 sb=0 sd=0
model=pfet_01v8
spiceprefix=X
}
C {xschem_sky130/sky130_fd_pr/nfet3_01v8.sym} 5860 4390 0 1 {name=M139
L=0.15
W=1
body=GND
nf=1
mult=1
ad="'int((nf+1)/2) * W/nf * 0.29'" 
pd="'2*int((nf+1)/2) * (W/nf + 0.29)'"
as="'int((nf+2)/2) * W/nf * 0.29'" 
ps="'2*int((nf+2)/2) * (W/nf + 0.29)'"
nrd="'0.29 / W'" nrs="'0.29 / W'"
sa=0 sb=0 sd=0
model=nfet_01v8
spiceprefix=X
}
C {xschem_sky130/sky130_fd_pr/pfet3_01v8.sym} 5680 4390 0 0 {name=M140
L=0.15
W=1
body=VDD
nf=1
mult=2
ad="'int((nf+1)/2) * W/nf * 0.29'" 
pd="'2*int((nf+1)/2) * (W/nf + 0.29)'"
as="'int((nf+2)/2) * W/nf * 0.29'" 
ps="'2*int((nf+2)/2) * (W/nf + 0.29)'"
nrd="'0.29 / W'" nrs="'0.29 / W'"
sa=0 sb=0 sd=0
model=pfet_01v8
spiceprefix=X
}
C {xschem_sky130/sky130_fd_pr/nfet3_01v8.sym} 5450 4300 1 1 {name=M141
L=0.15
W=1
body=GND
nf=1
mult=1
ad="'int((nf+1)/2) * W/nf * 0.29'" 
pd="'2*int((nf+1)/2) * (W/nf + 0.29)'"
as="'int((nf+2)/2) * W/nf * 0.29'" 
ps="'2*int((nf+2)/2) * (W/nf + 0.29)'"
nrd="'0.29 / W'" nrs="'0.29 / W'"
sa=0 sb=0 sd=0
model=nfet_01v8
spiceprefix=X
}
C {xschem_sky130/sky130_fd_pr/pfet3_01v8.sym} 5450 4120 1 0 {name=M142
L=0.15
W=1
body=VDD
nf=1
mult=2
ad="'int((nf+1)/2) * W/nf * 0.29'" 
pd="'2*int((nf+1)/2) * (W/nf + 0.29)'"
as="'int((nf+2)/2) * W/nf * 0.29'" 
ps="'2*int((nf+2)/2) * (W/nf + 0.29)'"
nrd="'0.29 / W'" nrs="'0.29 / W'"
sa=0 sb=0 sd=0
model=pfet_01v8
spiceprefix=X
}
C {xschem_sky130/sky130_fd_pr/nfet3_01v8.sym} 5450 4640 1 1 {name=M143
L=0.15
W=1
body=GND
nf=1
mult=1
ad="'int((nf+1)/2) * W/nf * 0.29'" 
pd="'2*int((nf+1)/2) * (W/nf + 0.29)'"
as="'int((nf+2)/2) * W/nf * 0.29'" 
ps="'2*int((nf+2)/2) * (W/nf + 0.29)'"
nrd="'0.29 / W'" nrs="'0.29 / W'"
sa=0 sb=0 sd=0
model=nfet_01v8
spiceprefix=X
}
C {xschem_sky130/sky130_fd_pr/pfet3_01v8.sym} 5450 4460 1 0 {name=M144
L=0.15
W=1
body=VDD
nf=1
mult=2
ad="'int((nf+1)/2) * W/nf * 0.29'" 
pd="'2*int((nf+1)/2) * (W/nf + 0.29)'"
as="'int((nf+2)/2) * W/nf * 0.29'" 
ps="'2*int((nf+2)/2) * (W/nf + 0.29)'"
nrd="'0.29 / W'" nrs="'0.29 / W'"
sa=0 sb=0 sd=0
model=pfet_01v8
spiceprefix=X
}
C {lab_pin.sym} 5180 4310 1 0 {name=l213 sig_type=std_logic lab=outpch1}
C {lab_pin.sym} 5180 4480 3 0 {name=l214 sig_type=std_logic lab=outp1}
C {lab_pin.sym} 5540 4540 1 0 {name=l215 sig_type=std_logic lab=outpch2}
C {lab_pin.sym} 5760 4470 3 0 {name=l216 sig_type=std_logic lab=outp2}
C {xschem_sky130/sky130_fd_pr/nfet3_01v8.sym} 5250 5200 0 1 {name=M145
L=0.15
W=1
body=GND
nf=1
mult=1
ad="'int((nf+1)/2) * W/nf * 0.29'" 
pd="'2*int((nf+1)/2) * (W/nf + 0.29)'"
as="'int((nf+2)/2) * W/nf * 0.29'" 
ps="'2*int((nf+2)/2) * (W/nf + 0.29)'"
nrd="'0.29 / W'" nrs="'0.29 / W'"
sa=0 sb=0 sd=0
model=nfet_01v8
spiceprefix=X
}
C {xschem_sky130/sky130_fd_pr/pfet3_01v8.sym} 5070 5200 0 0 {name=M146
L=0.15
W=1
body=VDD
nf=1
mult=2
ad="'int((nf+1)/2) * W/nf * 0.29'" 
pd="'2*int((nf+1)/2) * (W/nf + 0.29)'"
as="'int((nf+2)/2) * W/nf * 0.29'" 
ps="'2*int((nf+2)/2) * (W/nf + 0.29)'"
nrd="'0.29 / W'" nrs="'0.29 / W'"
sa=0 sb=0 sd=0
model=pfet_01v8
spiceprefix=X
}
C {xschem_sky130/sky130_fd_pr/nfet3_01v8.sym} 5830 5190 0 1 {name=M147
L=0.15
W=1
body=GND
nf=1
mult=1
ad="'int((nf+1)/2) * W/nf * 0.29'" 
pd="'2*int((nf+1)/2) * (W/nf + 0.29)'"
as="'int((nf+2)/2) * W/nf * 0.29'" 
ps="'2*int((nf+2)/2) * (W/nf + 0.29)'"
nrd="'0.29 / W'" nrs="'0.29 / W'"
sa=0 sb=0 sd=0
model=nfet_01v8
spiceprefix=X
}
C {xschem_sky130/sky130_fd_pr/pfet3_01v8.sym} 5650 5190 0 0 {name=M148
L=0.15
W=1
body=VDD
nf=1
mult=2
ad="'int((nf+1)/2) * W/nf * 0.29'" 
pd="'2*int((nf+1)/2) * (W/nf + 0.29)'"
as="'int((nf+2)/2) * W/nf * 0.29'" 
ps="'2*int((nf+2)/2) * (W/nf + 0.29)'"
nrd="'0.29 / W'" nrs="'0.29 / W'"
sa=0 sb=0 sd=0
model=pfet_01v8
spiceprefix=X
}
C {xschem_sky130/sky130_fd_pr/nfet3_01v8.sym} 5420 5100 1 1 {name=M149
L=0.15
W=1
body=GND
nf=1
mult=1
ad="'int((nf+1)/2) * W/nf * 0.29'" 
pd="'2*int((nf+1)/2) * (W/nf + 0.29)'"
as="'int((nf+2)/2) * W/nf * 0.29'" 
ps="'2*int((nf+2)/2) * (W/nf + 0.29)'"
nrd="'0.29 / W'" nrs="'0.29 / W'"
sa=0 sb=0 sd=0
model=nfet_01v8
spiceprefix=X
}
C {xschem_sky130/sky130_fd_pr/pfet3_01v8.sym} 5420 4920 1 0 {name=M150
L=0.15
W=1
body=VDD
nf=1
mult=2
ad="'int((nf+1)/2) * W/nf * 0.29'" 
pd="'2*int((nf+1)/2) * (W/nf + 0.29)'"
as="'int((nf+2)/2) * W/nf * 0.29'" 
ps="'2*int((nf+2)/2) * (W/nf + 0.29)'"
nrd="'0.29 / W'" nrs="'0.29 / W'"
sa=0 sb=0 sd=0
model=pfet_01v8
spiceprefix=X
}
C {xschem_sky130/sky130_fd_pr/nfet3_01v8.sym} 5420 5440 1 1 {name=M151
L=0.15
W=1
body=GND
nf=1
mult=1
ad="'int((nf+1)/2) * W/nf * 0.29'" 
pd="'2*int((nf+1)/2) * (W/nf + 0.29)'"
as="'int((nf+2)/2) * W/nf * 0.29'" 
ps="'2*int((nf+2)/2) * (W/nf + 0.29)'"
nrd="'0.29 / W'" nrs="'0.29 / W'"
sa=0 sb=0 sd=0
model=nfet_01v8
spiceprefix=X
}
C {xschem_sky130/sky130_fd_pr/pfet3_01v8.sym} 5420 5260 1 0 {name=M152
L=0.15
W=1
body=VDD
nf=1
mult=2
ad="'int((nf+1)/2) * W/nf * 0.29'" 
pd="'2*int((nf+1)/2) * (W/nf + 0.29)'"
as="'int((nf+2)/2) * W/nf * 0.29'" 
ps="'2*int((nf+2)/2) * (W/nf + 0.29)'"
nrd="'0.29 / W'" nrs="'0.29 / W'"
sa=0 sb=0 sd=0
model=pfet_01v8
spiceprefix=X
}
C {lab_pin.sym} 5150 5110 1 0 {name=l217 sig_type=std_logic lab=outnch1}
C {lab_pin.sym} 5150 5280 3 0 {name=l218 sig_type=std_logic lab=outn1}
C {lab_pin.sym} 5510 5340 1 0 {name=l219 sig_type=std_logic lab=outnch2}
C {lab_pin.sym} 5730 5270 3 0 {name=l220 sig_type=std_logic lab=outn2}
C {lab_pin.sym} 2480 5220 0 0 {name=l5 sig_type=std_logic lab=FvcoBy4_QPH_bar}
C {lab_pin.sym} 2560 4470 0 0 {name=l6 sig_type=std_logic lab=FvcoBy4_QPH_bar}
C {lab_pin.sym} 5000 4400 0 0 {name=l7 sig_type=std_logic lab=FvcoBy4_QPH_bar}
C {lab_pin.sym} 4990 5200 3 0 {name=l8 sig_type=std_logic lab=FvcoBy4_QPH_bar}
C {lab_pin.sym} 2570 4670 0 0 {name=l9 sig_type=std_logic lab=FvcoBy4_QPH}
C {lab_pin.sym} 2490 5430 0 0 {name=l10 sig_type=std_logic lab=FvcoBy4_QPH}
C {lab_pin.sym} 4980 5390 0 0 {name=l11 sig_type=std_logic lab=FvcoBy4_QPH}
C {lab_pin.sym} 5000 4580 0 0 {name=l12 sig_type=std_logic lab=FvcoBy4_QPH}
C {ipin.sym} 4020 4540 3 0 {name=p1 lab=vbp1}
C {ipin.sym} 4640 5010 3 0 {name=p2 lab=vbp2}
C {ipin.sym} 4600 4300 3 0 {name=p3 lab=vbn1}
C {ipin.sym} 2500 5230 1 0 {name=p4 lab=FvcoBy4_QPH_bar}
C {ipin.sym} 2530 5440 1 0 {name=p5 lab=FvcoBy4_QPH}
C {ipin.sym} 4060 4380 1 0 {name=p6 lab=VDD}
C {ipin.sym} 4580 4060 1 0 {name=p7 lab=VDD}
C {ipin.sym} 4660 4860 1 0 {name=p8 lab=VDD}
C {ipin.sym} 3800 5290 0 0 {name=p9 lab=GND}
C {lab_pin.sym} 3850 5140 0 0 {name=l1 sig_type=std_logic lab=GND}
C {lab_pin.sym} 4210 5140 0 0 {name=l2 sig_type=std_logic lab=GND}
C {lab_pin.sym} 4690 5270 0 0 {name=l3 sig_type=std_logic lab=GND}
C {lab_pin.sym} 3880 5290 2 0 {name=l4 sig_type=std_logic lab=GND}
C {lab_pin.sym} 4480 4340 0 0 {name=l13 sig_type=std_logic lab=GND}
C {lab_pin.sym} 4760 4340 2 0 {name=l14 sig_type=std_logic lab=GND}
C {opin.sym} 4410 4770 0 0 {name=p10 lab=Bout}
C {lab_pin.sym} 4650 4310 3 0 {name=l15 sig_type=std_logic lab=vbn1}
C {lab_pin.sym} 4100 4550 3 0 {name=l16 sig_type=std_logic lab=vbp1}
C {lab_pin.sym} 4700 5020 3 0 {name=l17 sig_type=std_logic lab=vbp2}
C {lab_pin.sym} 4350 4770 3 0 {name=l18 sig_type=std_logic lab=Bout}
C {lab_pin.sym} 3990 4370 1 0 {name=l19 sig_type=std_logic lab=VDD}
C {lab_pin.sym} 4510 4050 1 0 {name=l20 sig_type=std_logic lab=VDD}
C {lab_pin.sym} 4590 4850 1 0 {name=l21 sig_type=std_logic lab=VDD}
C {vsource.sym} 3560 5670 0 0 {name=V1 value="pulse(1.8 0 1u 10n 10n 2u 4u)"}
C {gnd.sym} 3560 5700 0 0 {name=l145 lab=GND}
C {vsource.sym} 3760 5870 0 0 {name=V2 value="pulse(0 1.8 1u 10n 10n 2u 4u)"}
C {gnd.sym} 3760 5900 0 0 {name=l147 lab=GND}
C {vsource.sym} 4550 5510 0 0 {name=V27 value=0.561}
C {gnd.sym} 4550 5540 0 0 {name=l394 lab=GND}
C {vsource.sym} 4260 5560 0 0 {name=V28 value=0.8}
C {gnd.sym} 4260 5590 0 0 {name=l395 lab=GND}
C {vsource.sym} 4420 5560 0 0 {name=V29 value=1.08}
C {gnd.sym} 4420 5590 0 0 {name=l396 lab=GND}
C {lab_pin.sym} 4260 5480 1 0 {name=l22 sig_type=std_logic lab=vbp1}
C {lab_pin.sym} 4420 5430 1 0 {name=l23 sig_type=std_logic lab=vbp2}
C {lab_pin.sym} 4550 5420 1 0 {name=l24 sig_type=std_logic lab=vbn1}
C {lab_pin.sym} 3640 5560 1 0 {name=l25 sig_type=std_logic lab=FvcoBy4_QPH}
C {lab_pin.sym} 3830 5620 1 0 {name=l26 sig_type=std_logic lab=FvcoBy4_QPH_bar}
